VERSION 5.7 ;
BUSBITCHARS "[]" ;
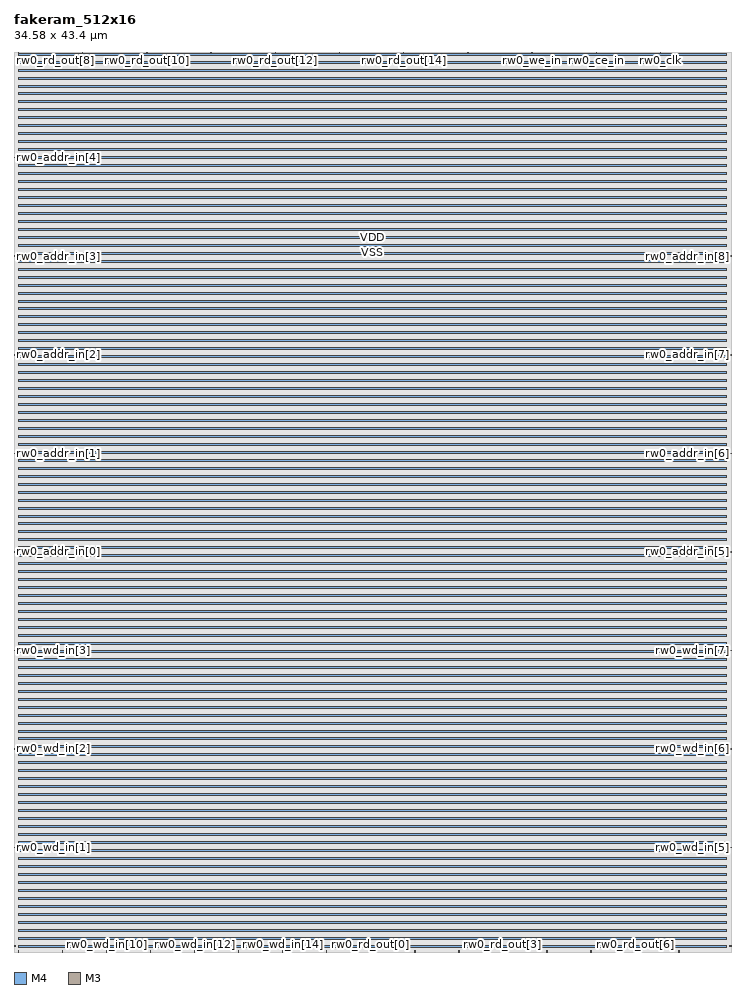
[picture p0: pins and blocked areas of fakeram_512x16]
MACRO fakeram_512x16
  FOREIGN fakeram_512x16 0 0 ;
  SYMMETRY X Y R90 ;
  SIZE 34.580 BY 43.400 ;
  CLASS BLOCK ;
  PIN rw0_wd_in[0]
    DIRECTION INPUT ;
    USE SIGNAL ;
    SHAPE ABUTMENT ;
    PORT
      LAYER M4 ;
      RECT 0.000 0.276 0.072 0.300 ;
    END
  END rw0_wd_in[0]
  PIN rw0_wd_in[1]
    DIRECTION INPUT ;
    USE SIGNAL ;
    SHAPE ABUTMENT ;
    PORT
      LAYER M4 ;
      RECT 0.000 5.028 0.072 5.052 ;
    END
  END rw0_wd_in[1]
  PIN rw0_wd_in[2]
    DIRECTION INPUT ;
    USE SIGNAL ;
    SHAPE ABUTMENT ;
    PORT
      LAYER M4 ;
      RECT 0.000 9.780 0.072 9.804 ;
    END
  END rw0_wd_in[2]
  PIN rw0_wd_in[3]
    DIRECTION INPUT ;
    USE SIGNAL ;
    SHAPE ABUTMENT ;
    PORT
      LAYER M4 ;
      RECT 0.000 14.532 0.072 14.556 ;
    END
  END rw0_wd_in[3]
  PIN rw0_wd_in[4]
    DIRECTION INPUT ;
    USE SIGNAL ;
    SHAPE ABUTMENT ;
    PORT
      LAYER M4 ;
      RECT 34.508 0.276 34.580 0.300 ;
    END
  END rw0_wd_in[4]
  PIN rw0_wd_in[5]
    DIRECTION INPUT ;
    USE SIGNAL ;
    SHAPE ABUTMENT ;
    PORT
      LAYER M4 ;
      RECT 34.508 5.028 34.580 5.052 ;
    END
  END rw0_wd_in[5]
  PIN rw0_wd_in[6]
    DIRECTION INPUT ;
    USE SIGNAL ;
    SHAPE ABUTMENT ;
    PORT
      LAYER M4 ;
      RECT 34.508 9.780 34.580 9.804 ;
    END
  END rw0_wd_in[6]
  PIN rw0_wd_in[7]
    DIRECTION INPUT ;
    USE SIGNAL ;
    SHAPE ABUTMENT ;
    PORT
      LAYER M4 ;
      RECT 34.508 14.532 34.580 14.556 ;
    END
  END rw0_wd_in[7]
  PIN rw0_wd_in[8]
    DIRECTION INPUT ;
    USE SIGNAL ;
    SHAPE ABUTMENT ;
    PORT
      LAYER M3 ;
      RECT 0.207 0.000 0.225 0.054 ;
    END
  END rw0_wd_in[8]
  PIN rw0_wd_in[9]
    DIRECTION INPUT ;
    USE SIGNAL ;
    SHAPE ABUTMENT ;
    PORT
      LAYER M3 ;
      RECT 2.331 0.000 2.349 0.054 ;
    END
  END rw0_wd_in[9]
  PIN rw0_wd_in[10]
    DIRECTION INPUT ;
    USE SIGNAL ;
    SHAPE ABUTMENT ;
    PORT
      LAYER M3 ;
      RECT 4.455 0.000 4.473 0.054 ;
    END
  END rw0_wd_in[10]
  PIN rw0_wd_in[11]
    DIRECTION INPUT ;
    USE SIGNAL ;
    SHAPE ABUTMENT ;
    PORT
      LAYER M3 ;
      RECT 6.579 0.000 6.597 0.054 ;
    END
  END rw0_wd_in[11]
  PIN rw0_wd_in[12]
    DIRECTION INPUT ;
    USE SIGNAL ;
    SHAPE ABUTMENT ;
    PORT
      LAYER M3 ;
      RECT 8.703 0.000 8.721 0.054 ;
    END
  END rw0_wd_in[12]
  PIN rw0_wd_in[13]
    DIRECTION INPUT ;
    USE SIGNAL ;
    SHAPE ABUTMENT ;
    PORT
      LAYER M3 ;
      RECT 10.827 0.000 10.845 0.054 ;
    END
  END rw0_wd_in[13]
  PIN rw0_wd_in[14]
    DIRECTION INPUT ;
    USE SIGNAL ;
    SHAPE ABUTMENT ;
    PORT
      LAYER M3 ;
      RECT 12.951 0.000 12.969 0.054 ;
    END
  END rw0_wd_in[14]
  PIN rw0_wd_in[15]
    DIRECTION INPUT ;
    USE SIGNAL ;
    SHAPE ABUTMENT ;
    PORT
      LAYER M3 ;
      RECT 15.075 0.000 15.093 0.054 ;
    END
  END rw0_wd_in[15]
  PIN rw0_rd_out[0]
    DIRECTION OUTPUT ;
    USE SIGNAL ;
    SHAPE ABUTMENT ;
    PORT
      LAYER M3 ;
      RECT 17.199 0.000 17.217 0.054 ;
    END
  END rw0_rd_out[0]
  PIN rw0_rd_out[1]
    DIRECTION OUTPUT ;
    USE SIGNAL ;
    SHAPE ABUTMENT ;
    PORT
      LAYER M3 ;
      RECT 19.323 0.000 19.341 0.054 ;
    END
  END rw0_rd_out[1]
  PIN rw0_rd_out[2]
    DIRECTION OUTPUT ;
    USE SIGNAL ;
    SHAPE ABUTMENT ;
    PORT
      LAYER M3 ;
      RECT 21.447 0.000 21.465 0.054 ;
    END
  END rw0_rd_out[2]
  PIN rw0_rd_out[3]
    DIRECTION OUTPUT ;
    USE SIGNAL ;
    SHAPE ABUTMENT ;
    PORT
      LAYER M3 ;
      RECT 23.571 0.000 23.589 0.054 ;
    END
  END rw0_rd_out[3]
  PIN rw0_rd_out[4]
    DIRECTION OUTPUT ;
    USE SIGNAL ;
    SHAPE ABUTMENT ;
    PORT
      LAYER M3 ;
      RECT 25.695 0.000 25.713 0.054 ;
    END
  END rw0_rd_out[4]
  PIN rw0_rd_out[5]
    DIRECTION OUTPUT ;
    USE SIGNAL ;
    SHAPE ABUTMENT ;
    PORT
      LAYER M3 ;
      RECT 27.819 0.000 27.837 0.054 ;
    END
  END rw0_rd_out[5]
  PIN rw0_rd_out[6]
    DIRECTION OUTPUT ;
    USE SIGNAL ;
    SHAPE ABUTMENT ;
    PORT
      LAYER M3 ;
      RECT 29.943 0.000 29.961 0.054 ;
    END
  END rw0_rd_out[6]
  PIN rw0_rd_out[7]
    DIRECTION OUTPUT ;
    USE SIGNAL ;
    SHAPE ABUTMENT ;
    PORT
      LAYER M3 ;
      RECT 32.067 0.000 32.085 0.054 ;
    END
  END rw0_rd_out[7]
  PIN rw0_rd_out[8]
    DIRECTION OUTPUT ;
    USE SIGNAL ;
    SHAPE ABUTMENT ;
    PORT
      LAYER M3 ;
      RECT 0.207 43.346 0.225 43.400 ;
    END
  END rw0_rd_out[8]
  PIN rw0_rd_out[9]
    DIRECTION OUTPUT ;
    USE SIGNAL ;
    SHAPE ABUTMENT ;
    PORT
      LAYER M3 ;
      RECT 3.303 43.346 3.321 43.400 ;
    END
  END rw0_rd_out[9]
  PIN rw0_rd_out[10]
    DIRECTION OUTPUT ;
    USE SIGNAL ;
    SHAPE ABUTMENT ;
    PORT
      LAYER M3 ;
      RECT 6.399 43.346 6.417 43.400 ;
    END
  END rw0_rd_out[10]
  PIN rw0_rd_out[11]
    DIRECTION OUTPUT ;
    USE SIGNAL ;
    SHAPE ABUTMENT ;
    PORT
      LAYER M3 ;
      RECT 9.495 43.346 9.513 43.400 ;
    END
  END rw0_rd_out[11]
  PIN rw0_rd_out[12]
    DIRECTION OUTPUT ;
    USE SIGNAL ;
    SHAPE ABUTMENT ;
    PORT
      LAYER M3 ;
      RECT 12.591 43.346 12.609 43.400 ;
    END
  END rw0_rd_out[12]
  PIN rw0_rd_out[13]
    DIRECTION OUTPUT ;
    USE SIGNAL ;
    SHAPE ABUTMENT ;
    PORT
      LAYER M3 ;
      RECT 15.687 43.346 15.705 43.400 ;
    END
  END rw0_rd_out[13]
  PIN rw0_rd_out[14]
    DIRECTION OUTPUT ;
    USE SIGNAL ;
    SHAPE ABUTMENT ;
    PORT
      LAYER M3 ;
      RECT 18.783 43.346 18.801 43.400 ;
    END
  END rw0_rd_out[14]
  PIN rw0_rd_out[15]
    DIRECTION OUTPUT ;
    USE SIGNAL ;
    SHAPE ABUTMENT ;
    PORT
      LAYER M3 ;
      RECT 21.879 43.346 21.897 43.400 ;
    END
  END rw0_rd_out[15]
  PIN rw0_addr_in[0]
    DIRECTION INPUT ;
    USE SIGNAL ;
    SHAPE ABUTMENT ;
    PORT
      LAYER M4 ;
      RECT 0.000 19.284 0.072 19.308 ;
    END
  END rw0_addr_in[0]
  PIN rw0_addr_in[1]
    DIRECTION INPUT ;
    USE SIGNAL ;
    SHAPE ABUTMENT ;
    PORT
      LAYER M4 ;
      RECT 0.000 24.036 0.072 24.060 ;
    END
  END rw0_addr_in[1]
  PIN rw0_addr_in[2]
    DIRECTION INPUT ;
    USE SIGNAL ;
    SHAPE ABUTMENT ;
    PORT
      LAYER M4 ;
      RECT 0.000 28.788 0.072 28.812 ;
    END
  END rw0_addr_in[2]
  PIN rw0_addr_in[3]
    DIRECTION INPUT ;
    USE SIGNAL ;
    SHAPE ABUTMENT ;
    PORT
      LAYER M4 ;
      RECT 0.000 33.540 0.072 33.564 ;
    END
  END rw0_addr_in[3]
  PIN rw0_addr_in[4]
    DIRECTION INPUT ;
    USE SIGNAL ;
    SHAPE ABUTMENT ;
    PORT
      LAYER M4 ;
      RECT 0.000 38.292 0.072 38.316 ;
    END
  END rw0_addr_in[4]
  PIN rw0_addr_in[5]
    DIRECTION INPUT ;
    USE SIGNAL ;
    SHAPE ABUTMENT ;
    PORT
      LAYER M4 ;
      RECT 34.508 19.284 34.580 19.308 ;
    END
  END rw0_addr_in[5]
  PIN rw0_addr_in[6]
    DIRECTION INPUT ;
    USE SIGNAL ;
    SHAPE ABUTMENT ;
    PORT
      LAYER M4 ;
      RECT 34.508 24.036 34.580 24.060 ;
    END
  END rw0_addr_in[6]
  PIN rw0_addr_in[7]
    DIRECTION INPUT ;
    USE SIGNAL ;
    SHAPE ABUTMENT ;
    PORT
      LAYER M4 ;
      RECT 34.508 28.788 34.580 28.812 ;
    END
  END rw0_addr_in[7]
  PIN rw0_addr_in[8]
    DIRECTION INPUT ;
    USE SIGNAL ;
    SHAPE ABUTMENT ;
    PORT
      LAYER M4 ;
      RECT 34.508 33.540 34.580 33.564 ;
    END
  END rw0_addr_in[8]
  PIN rw0_we_in
    DIRECTION INPUT ;
    USE SIGNAL ;
    SHAPE ABUTMENT ;
    PORT
      LAYER M3 ;
      RECT 24.975 43.346 24.993 43.400 ;
    END
  END rw0_we_in
  PIN rw0_ce_in
    DIRECTION INPUT ;
    USE SIGNAL ;
    SHAPE ABUTMENT ;
    PORT
      LAYER M3 ;
      RECT 28.071 43.346 28.089 43.400 ;
    END
  END rw0_ce_in
  PIN rw0_clk
    DIRECTION INPUT ;
    USE SIGNAL ;
    SHAPE ABUTMENT ;
    PORT
      LAYER M3 ;
      RECT 31.167 43.346 31.185 43.400 ;
    END
  END rw0_clk
  PIN VSS
    DIRECTION INOUT ;
    USE GROUND ;
    PORT
      LAYER M4 ;
      RECT 0.216 0.240 34.364 0.336 ;
      RECT 0.216 1.008 34.364 1.104 ;
      RECT 0.216 1.776 34.364 1.872 ;
      RECT 0.216 2.544 34.364 2.640 ;
      RECT 0.216 3.312 34.364 3.408 ;
      RECT 0.216 4.080 34.364 4.176 ;
      RECT 0.216 4.848 34.364 4.944 ;
      RECT 0.216 5.616 34.364 5.712 ;
      RECT 0.216 6.384 34.364 6.480 ;
      RECT 0.216 7.152 34.364 7.248 ;
      RECT 0.216 7.920 34.364 8.016 ;
      RECT 0.216 8.688 34.364 8.784 ;
      RECT 0.216 9.456 34.364 9.552 ;
      RECT 0.216 10.224 34.364 10.320 ;
      RECT 0.216 10.992 34.364 11.088 ;
      RECT 0.216 11.760 34.364 11.856 ;
      RECT 0.216 12.528 34.364 12.624 ;
      RECT 0.216 13.296 34.364 13.392 ;
      RECT 0.216 14.064 34.364 14.160 ;
      RECT 0.216 14.832 34.364 14.928 ;
      RECT 0.216 15.600 34.364 15.696 ;
      RECT 0.216 16.368 34.364 16.464 ;
      RECT 0.216 17.136 34.364 17.232 ;
      RECT 0.216 17.904 34.364 18.000 ;
      RECT 0.216 18.672 34.364 18.768 ;
      RECT 0.216 19.440 34.364 19.536 ;
      RECT 0.216 20.208 34.364 20.304 ;
      RECT 0.216 20.976 34.364 21.072 ;
      RECT 0.216 21.744 34.364 21.840 ;
      RECT 0.216 22.512 34.364 22.608 ;
      RECT 0.216 23.280 34.364 23.376 ;
      RECT 0.216 24.048 34.364 24.144 ;
      RECT 0.216 24.816 34.364 24.912 ;
      RECT 0.216 25.584 34.364 25.680 ;
      RECT 0.216 26.352 34.364 26.448 ;
      RECT 0.216 27.120 34.364 27.216 ;
      RECT 0.216 27.888 34.364 27.984 ;
      RECT 0.216 28.656 34.364 28.752 ;
      RECT 0.216 29.424 34.364 29.520 ;
      RECT 0.216 30.192 34.364 30.288 ;
      RECT 0.216 30.960 34.364 31.056 ;
      RECT 0.216 31.728 34.364 31.824 ;
      RECT 0.216 32.496 34.364 32.592 ;
      RECT 0.216 33.264 34.364 33.360 ;
      RECT 0.216 34.032 34.364 34.128 ;
      RECT 0.216 34.800 34.364 34.896 ;
      RECT 0.216 35.568 34.364 35.664 ;
      RECT 0.216 36.336 34.364 36.432 ;
      RECT 0.216 37.104 34.364 37.200 ;
      RECT 0.216 37.872 34.364 37.968 ;
      RECT 0.216 38.640 34.364 38.736 ;
      RECT 0.216 39.408 34.364 39.504 ;
      RECT 0.216 40.176 34.364 40.272 ;
      RECT 0.216 40.944 34.364 41.040 ;
      RECT 0.216 41.712 34.364 41.808 ;
      RECT 0.216 42.480 34.364 42.576 ;
      RECT 0.216 43.248 34.364 43.344 ;
    END
  END VSS
  PIN VDD
    DIRECTION INOUT ;
    USE POWER ;
    PORT
      LAYER M4 ;
      RECT 0.216 0.624 34.364 0.720 ;
      RECT 0.216 1.392 34.364 1.488 ;
      RECT 0.216 2.160 34.364 2.256 ;
      RECT 0.216 2.928 34.364 3.024 ;
      RECT 0.216 3.696 34.364 3.792 ;
      RECT 0.216 4.464 34.364 4.560 ;
      RECT 0.216 5.232 34.364 5.328 ;
      RECT 0.216 6.000 34.364 6.096 ;
      RECT 0.216 6.768 34.364 6.864 ;
      RECT 0.216 7.536 34.364 7.632 ;
      RECT 0.216 8.304 34.364 8.400 ;
      RECT 0.216 9.072 34.364 9.168 ;
      RECT 0.216 9.840 34.364 9.936 ;
      RECT 0.216 10.608 34.364 10.704 ;
      RECT 0.216 11.376 34.364 11.472 ;
      RECT 0.216 12.144 34.364 12.240 ;
      RECT 0.216 12.912 34.364 13.008 ;
      RECT 0.216 13.680 34.364 13.776 ;
      RECT 0.216 14.448 34.364 14.544 ;
      RECT 0.216 15.216 34.364 15.312 ;
      RECT 0.216 15.984 34.364 16.080 ;
      RECT 0.216 16.752 34.364 16.848 ;
      RECT 0.216 17.520 34.364 17.616 ;
      RECT 0.216 18.288 34.364 18.384 ;
      RECT 0.216 19.056 34.364 19.152 ;
      RECT 0.216 19.824 34.364 19.920 ;
      RECT 0.216 20.592 34.364 20.688 ;
      RECT 0.216 21.360 34.364 21.456 ;
      RECT 0.216 22.128 34.364 22.224 ;
      RECT 0.216 22.896 34.364 22.992 ;
      RECT 0.216 23.664 34.364 23.760 ;
      RECT 0.216 24.432 34.364 24.528 ;
      RECT 0.216 25.200 34.364 25.296 ;
      RECT 0.216 25.968 34.364 26.064 ;
      RECT 0.216 26.736 34.364 26.832 ;
      RECT 0.216 27.504 34.364 27.600 ;
      RECT 0.216 28.272 34.364 28.368 ;
      RECT 0.216 29.040 34.364 29.136 ;
      RECT 0.216 29.808 34.364 29.904 ;
      RECT 0.216 30.576 34.364 30.672 ;
      RECT 0.216 31.344 34.364 31.440 ;
      RECT 0.216 32.112 34.364 32.208 ;
      RECT 0.216 32.880 34.364 32.976 ;
      RECT 0.216 33.648 34.364 33.744 ;
      RECT 0.216 34.416 34.364 34.512 ;
      RECT 0.216 35.184 34.364 35.280 ;
      RECT 0.216 35.952 34.364 36.048 ;
      RECT 0.216 36.720 34.364 36.816 ;
      RECT 0.216 37.488 34.364 37.584 ;
      RECT 0.216 38.256 34.364 38.352 ;
      RECT 0.216 39.024 34.364 39.120 ;
      RECT 0.216 39.792 34.364 39.888 ;
      RECT 0.216 40.560 34.364 40.656 ;
      RECT 0.216 41.328 34.364 41.424 ;
      RECT 0.216 42.096 34.364 42.192 ;
      RECT 0.216 42.864 34.364 42.960 ;
    END
  END VDD
  OBS
    LAYER M1 ;
    RECT 0 0 34.580 43.400 ;
    LAYER M2 ;
    RECT 0 0 34.580 43.400 ;
    LAYER M3 ;
    RECT 0 0 34.580 43.400 ;
    LAYER M4 ;
    RECT 0 0 34.580 43.400 ;
  END
END fakeram_512x16

END LIBRARY
